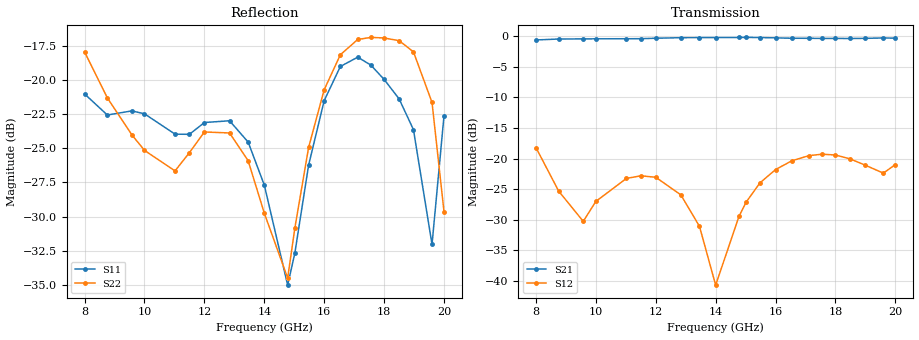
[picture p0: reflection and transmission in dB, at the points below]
! MS46524B
! 12345/M1: Not Set/M2: Not Set
! 3/11/2021 9:41:28 PM
! D:\WEBSITE FILES\DATASHEETS\MEASURED DATA\8.0 - 20.0 GHZ (D4I8020).S2P
! CHANNEL.1
! TR.MEASUREMENT
! RAW.DATA
# GHZ S RI R 50.0
! FREQ.GHZ  S11RE  S11IM  S21RE  S21IM  S12RE  S12IM  S22RE  S22IM
!; PortSelection: Port_12
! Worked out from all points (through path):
!   601 points, 8 GHz to 20 GHz, reference 50 ohm
!   highest |S21| = -0.22 dB at 15.02 GHz (marker M1); lowest = -0.6 dB at 8 GHz (marker M2)
!   lowest |S11| = -35.0 dB at 14.78 GHz (marker M3), VSWR 1.04, Z = 49.7 + j1.74 ohm
!   |S11| at or under -10 dB: start of sweep to end of sweep
!   |S22| runs from -36.0 to -16.9 dB; largest |S21 - S12| = 1
!   S11 on the Smith chart (normalised r, x): 8 GHz: 0.84, +0.05; 9.58 GHz: 1.16, +0.04; 20 GHz: 0.88, +0.07
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8  -0.0841 0.0284  -0.6568 -0.6574  -0.0169 0.1217  -0.1245 0.0221
8.76  0.0135 0.0731  -0.9282 0.1814  0.039 0.0376  -0.0251 0.0821
9.58  0.0755 0.015  -0.3203 0.8927  0.019 0.0241  0.0499 0.0383
10  0.0708 -0.025  0.1698 0.9343  0.0337 0.0293  0.0552 0.000276
11.02  -0.0105 -0.0624  0.9413 0.1351  0.0578 -0.0373  -0.00828 -0.0457
11.5  -0.0501 -0.0385  0.861 -0.4057  0.0211 -0.0691  -0.0455 -0.0294
12  -0.0691 0.00976  0.4809 -0.8308  -0.0321 -0.0626  -0.0635 0.011
12.84  -0.0267 0.0656  -0.4686 -0.8493  -0.0483 0.0145  -0.0236 0.0594
13.46  0.00917 0.0585  -0.9264 -0.2914  -0.00437 0.0276  0.00654 0.0502
14  0.0178 0.0372  -0.9108 0.34  0.00925 -0.000327  0.0119 0.0303
14.78  -0.00304 0.0175  -0.2463 0.9424  -0.0329 -0.00749  -0.0124 0.0142
15.02  -0.0146 0.0181  0.0415 0.9745  -0.0431 0.0096  -0.0239 0.0159
15.48  -0.0375 0.0312  0.5579 0.7964  -0.0333 0.0538  -0.0461 0.0329
16  -0.0487 0.0684  0.9185 0.3018  0.025 0.0773  -0.0555 0.0734
16.54  -0.0272 0.1085  0.9013 -0.3292  0.0889 0.0356  -0.0329 0.119
17.12  0.0194 0.1194  0.4653 -0.8382  0.0896 -0.0561  0.0165 0.1394
17.56  0.0449 0.1038  -0.0399 -0.9556  0.0328 -0.1034  0.0501 0.1338
18  0.0545 0.0842  -0.5351 -0.7929  -0.0411 -0.0986  0.0764 0.1199
18.5  0.0554 0.0647  -0.8962 -0.3311  -0.0914 -0.0385  0.101 0.0955
18.98  0.0481 0.0448  -0.9253 0.246  -0.0847 0.0258  0.1127 0.0575
19.6  -0.000844 0.025  -0.4601 0.8485  -0.0405 0.0643  0.0825 0.00426
20  -0.0611 0.0416  0.0531 0.9591  -0.0247 0.0859  0.0276 -0.018
